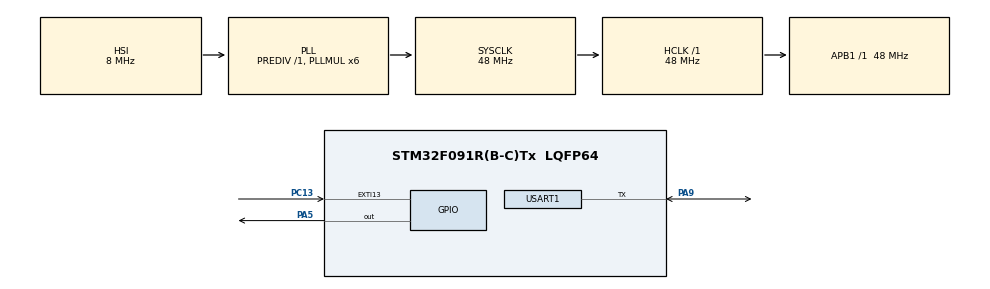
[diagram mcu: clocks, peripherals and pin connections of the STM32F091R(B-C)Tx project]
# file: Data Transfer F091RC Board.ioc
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Dma.Request0=USART1_RX
Dma.Request1=USART1_TX
Dma.USART1_RX.0.Direction=DMA_PERIPH_TO_MEMORY
Dma.USART1_RX.0.Instance=DMA1_Channel1
Dma.USART1_RX.0.MemDataAlignment=DMA_MDATAALIGN_BYTE
Dma.USART1_RX.0.MemInc=DMA_MINC_ENABLE
Dma.USART1_RX.0.Mode=DMA_NORMAL
Dma.USART1_RX.0.PeriphDataAlignment=DMA_PDATAALIGN_BYTE
Dma.USART1_RX.0.PeriphInc=DMA_PINC_DISABLE
Dma.USART1_RX.0.Priority=DMA_PRIORITY_LOW
Dma.USART1_TX.1.Direction=DMA_MEMORY_TO_PERIPH
Dma.USART1_TX.1.Instance=DMA1_Channel2
Dma.USART1_TX.1.MemDataAlignment=DMA_MDATAALIGN_BYTE
Dma.USART1_TX.1.MemInc=DMA_MINC_ENABLE
Dma.USART1_TX.1.Mode=DMA_NORMAL
Dma.USART1_TX.1.PeriphDataAlignment=DMA_PDATAALIGN_BYTE
Dma.USART1_TX.1.PeriphInc=DMA_PINC_DISABLE
Dma.USART1_TX.1.Priority=DMA_PRIORITY_LOW
Mcu.Family=STM32F0
Mcu.Name=STM32F091R(B-C)Tx
Mcu.Package=LQFP64
NVIC.DMA1_Ch1_IRQn=true\:0\:0\:false\:false\:true\:false\:true\:true
NVIC.DMA1_Ch2_3_DMA2_Ch1_2_IRQn=true\:0\:0\:false\:false\:true\:false\:true\:true
NVIC.EXTI4_15_IRQn=true\:0\:0\:false\:false\:true\:true\:true\:true
NVIC.USART1_IRQn=true\:0\:0\:false\:false\:true\:true\:true\:true
PA13.GPIO_Label=TMS
PA13.Mode=Serial_Wire
PA13.Signal=SYS_SWDIO
PA14.GPIO_Label=TCK
PA14.Mode=Serial_Wire
PA14.Signal=SYS_SWCLK
PA3.GPIO_Label=USART_RX
PA3.GPIO_Mode=GPIO_MODE_AF_PP
PA3.GPIO_PuPd=GPIO_NOPULL
PA3.GPIO_Speed=GPIO_SPEED_FREQ_LOW
PA3.Signal=USART2_RX
PA5.Signal=GPIO_Output
PA9.Mode=Half_duplex(single_wire_mode)
PA9.Signal=USART1_TX
PC13.GPIO_ModeDefaultEXTI=GPIO_MODE_IT_RISING
PC13.GPIO_PuPd=GPIO_PULLUP
PC13.Signal=GPXTI13
PC14OSC32_IN.Mode=LSE-External-Oscillator
PC14OSC32_IN.Signal=RCC_OSC32_IN
PC15OSC32_OUT.Mode=LSE-External-Oscillator
PC15OSC32_OUT.Signal=RCC_OSC32_OUT
PF0-OSC_IN.Mode=HSE-External-Clock-Source
PF0-OSC_IN.Signal=RCC_OSC_IN
PF1-OSC_OUT.Signal=RCC_OSC_OUT
ProjectManager.HeapSize=0x200
ProjectManager.StackSize=0x400
ProjectManager.TargetToolchain=STM32CubeIDE
RCC.AHBFreq_Value=48000000
RCC.APB1Freq_Value=48000000
RCC.APB1TimFreq_Value=48000000
RCC.FLatency-AdvancedSettings=FLASH_LATENCY_1
RCC.HCLKFreq_Value=48000000
RCC.PLLMUL=RCC_PLL_MUL6
RCC.PREFETCH_ENABLE-AdvancedSettings=1
RCC.SYSCLKFreq_VALUE=48000000
RCC.SYSCLKSource=RCC_SYSCLKSOURCE_PLLCLK
USART1.BaudRate=9600
USART1.VirtualMode-Half_duplex(single_wire_mode)=VM_ASYNC
board=NUCLEO-F091RC

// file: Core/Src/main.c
#include "main.h"
#include "stdio.h"

UART_HandleTypeDef huart1;
DMA_HandleTypeDef hdma_usart1_rx;
DMA_HandleTypeDef hdma_usart1_tx;

void SystemClock_Config(void);
static void MX_GPIO_Init(void);
static void MX_DMA_Init(void);
static void MX_USART1_UART_Init(void);
void DisplayHex(uint8_t value);

const uint8_t segmentMap[16] = {
	0b00111111, // 0
	0b00000110, // 1
	0b01011011, // 2
	0b01001111, // 3
	0b01100110, // 4
	0b01101101, // 5
	0b01111101, // 6
	0b00000111, // 7
	0b01111111, // 8
	0b01101111, // 9
	0b01110111, // A
	0b01111100, // B
	0b00111001, // C
	0b01011110, // D
	0b01111001, // E
	0b01110001  // F
};

typedef enum {
    STATE_IDLE,
    STATE_SEND_UART,
	STATE_PROCESS_RX
} SystemState_t;

SystemState_t currentState = STATE_IDLE;

uint8_t RxData[1];
uint8_t TxData[1];
uint8_t receivedValue = 0;
uint8_t rxFlag = 0;
uint8_t count = 0;
uint8_t isClicked = 0;

void HAL_UARTEx_RxEventCallback(UART_HandleTypeDef *huart, uint16_t Size)
{
	if (huart->Instance == USART1)
	    {
		receivedValue = RxData[0];
		rxFlag = 1;

		HAL_UARTEx_ReceiveToIdle_IT(&huart1, RxData, 1);
	    }
}

void HAL_GPIO_EXTI_Callback(uint16_t GPIO_Pin)
{
	if (GPIO_Pin == GPIO_PIN_13)
	{
		isClicked = 1;
	}
}

int main(void)
{
  HAL_Init();
  SystemClock_Config();
  MX_GPIO_Init();
  MX_DMA_Init();
  MX_USART1_UART_Init();

  HAL_HalfDuplex_EnableReceiver(&huart1);
  HAL_UARTEx_ReceiveToIdle_IT(&huart1, RxData, 1);

  DisplayHex(count);

  while (1)
  {
  switch (currentState)
	  {
	  case STATE_IDLE:
		  if (isClicked)
		  {
			  currentState = STATE_SEND_UART;
		  } else if (rxFlag)
		  {
			  currentState = STATE_PROCESS_RX;
		  }
		  break;

	  case STATE_SEND_UART:
	  {
		  HAL_Delay(100); // debounce

		  TxData[0] = count;
		  HAL_HalfDuplex_EnableTransmitter(&huart1);
		  HAL_UART_Transmit(&huart1, TxData, 1, 1000);
		  HAL_HalfDuplex_EnableReceiver(&huart1);

		  isClicked = 0;
		  currentState = STATE_IDLE;
		  break;
	   }

	  case STATE_PROCESS_RX:
	  {
		  count = receivedValue + 1;
		  if (count > 15)
		  {
			  count = 0;
		  }
		  DisplayHex(count);
		  rxFlag = 0;

		  currentState = STATE_IDLE;
		  break;
	  }

	  default:
		  currentState = STATE_IDLE;
		  break;
	  }
   }
}

void DisplayHex(uint8_t value)
{
    uint8_t segments = segmentMap[value];

    // PA0(A), PA1(B), PA4(E), PA5(F), PA6(G)
    HAL_GPIO_WritePin(GPIOA, GPIO_PIN_0, (segments & (1<<0)) ? GPIO_PIN_RESET : GPIO_PIN_SET);
    HAL_GPIO_WritePin(GPIOA, GPIO_PIN_1, (segments & (1<<1)) ? GPIO_PIN_RESET : GPIO_PIN_SET);
    HAL_GPIO_WritePin(GPIOA, GPIO_PIN_4, (segments & (1<<4)) ? GPIO_PIN_RESET : GPIO_PIN_SET);
    HAL_GPIO_WritePin(GPIOA, GPIO_PIN_5, (segments & (1<<5)) ? GPIO_PIN_RESET : GPIO_PIN_SET);
    HAL_GPIO_WritePin(GPIOA, GPIO_PIN_6, (segments & (1<<6)) ? GPIO_PIN_RESET : GPIO_PIN_SET);

    // PC10(C), PC11(D)
    HAL_GPIO_WritePin(GPIOC, GPIO_PIN_10, (segments & (1<<2)) ? GPIO_PIN_RESET : GPIO_PIN_SET);
    HAL_GPIO_WritePin(GPIOC, GPIO_PIN_11, (segments & (1<<3)) ? GPIO_PIN_RESET : GPIO_PIN_SET);
}

void SystemClock_Config(void)
{
  RCC_OscInitTypeDef RCC_OscInitStruct = {0};
  RCC_ClkInitTypeDef RCC_ClkInitStruct = {0};
  RCC_PeriphCLKInitTypeDef PeriphClkInit = {0};

  /** Initializes the RCC Oscillators according to the specified parameters
  * in the RCC_OscInitTypeDef structure.
  */
  RCC_OscInitStruct.OscillatorType = RCC_OSCILLATORTYPE_HSI;
  RCC_OscInitStruct.HSIState = RCC_HSI_ON;
  RCC_OscInitStruct.HSICalibrationValue = RCC_HSICALIBRATION_DEFAULT;
  RCC_OscInitStruct.PLL.PLLState = RCC_PLL_ON;
  RCC_OscInitStruct.PLL.PLLSource = RCC_PLLSOURCE_HSI;
  RCC_OscInitStruct.PLL.PLLMUL = RCC_PLL_MUL6;
  RCC_OscInitStruct.PLL.PREDIV = RCC_PREDIV_DIV1;
  if (HAL_RCC_OscConfig(&RCC_OscInitStruct) != HAL_OK)
  {
    Error_Handler();
  }

  /** Initializes the CPU, AHB and APB buses clocks
  */
  RCC_ClkInitStruct.ClockType = RCC_CLOCKTYPE_HCLK|RCC_CLOCKTYPE_SYSCLK
                              |RCC_CLOCKTYPE_PCLK1;
  RCC_ClkInitStruct.SYSCLKSource = RCC_SYSCLKSOURCE_PLLCLK;
  RCC_ClkInitStruct.AHBCLKDivider = RCC_SYSCLK_DIV1;
  RCC_ClkInitStruct.APB1CLKDivider = RCC_HCLK_DIV1;

  if (HAL_RCC_ClockConfig(&RCC_ClkInitStruct, FLASH_LATENCY_1) != HAL_OK)
  {
    Error_Handler();
  }
  PeriphClkInit.PeriphClockSelection = RCC_PERIPHCLK_USART1;
  PeriphClkInit.Usart1ClockSelection = RCC_USART1CLKSOURCE_PCLK1;
  if (HAL_RCCEx_PeriphCLKConfig(&PeriphClkInit) != HAL_OK)
  {
    Error_Handler();
  }
}

static void MX_USART1_UART_Init(void)
{
  huart1.Instance = USART1;
  huart1.Init.BaudRate = 9600;
  huart1.Init.WordLength = UART_WORDLENGTH_8B;
  huart1.Init.StopBits = UART_STOPBITS_1;
  huart1.Init.Parity = UART_PARITY_NONE;
  huart1.Init.Mode = UART_MODE_TX_RX;
  huart1.Init.HwFlowCtl = UART_HWCONTROL_NONE;
  huart1.Init.OverSampling = UART_OVERSAMPLING_16;
  huart1.Init.OneBitSampling = UART_ONE_BIT_SAMPLE_DISABLE;
  huart1.AdvancedInit.AdvFeatureInit = UART_ADVFEATURE_NO_INIT;
  if (HAL_HalfDuplex_Init(&huart1) != HAL_OK)
  {
    Error_Handler();
  }
}

static void MX_DMA_Init(void)
{

  /* DMA controller clock enable */
  __HAL_RCC_DMA1_CLK_ENABLE();

  /* DMA interrupt init */
  /* DMA1_Ch1_IRQn interrupt configuration */
  HAL_NVIC_SetPriority(DMA1_Ch1_IRQn, 0, 0);
  HAL_NVIC_EnableIRQ(DMA1_Ch1_IRQn);
  /* DMA1_Ch2_3_DMA2_Ch1_2_IRQn interrupt configuration */
  HAL_NVIC_SetPriority(DMA1_Ch2_3_DMA2_Ch1_2_IRQn, 0, 0);
  HAL_NVIC_EnableIRQ(DMA1_Ch2_3_DMA2_Ch1_2_IRQn);

}

static void MX_GPIO_Init(void)
{
  GPIO_InitTypeDef GPIO_InitStruct = {0};
  /* GPIO Ports Clock Enable */
  __HAL_RCC_GPIOC_CLK_ENABLE();
  __HAL_RCC_GPIOF_CLK_ENABLE();
  __HAL_RCC_GPIOA_CLK_ENABLE();
  __HAL_RCC_GPIOB_CLK_ENABLE();

  /*Configure GPIO pin Output Level */
  HAL_GPIO_WritePin(GPIOA, GPIO_PIN_5, GPIO_PIN_RESET);

  /*Configure GPIO pin : PC13 */
  GPIO_InitStruct.Pin = GPIO_PIN_13;
  GPIO_InitStruct.Mode = GPIO_MODE_IT_RISING;
  GPIO_InitStruct.Pull = GPIO_PULLUP;
  HAL_GPIO_Init(GPIOC, &GPIO_InitStruct);

  /*Configure GPIO pin : USART_RX_Pin */
  GPIO_InitStruct.Pin = USART_RX_Pin;
  GPIO_InitStruct.Mode = GPIO_MODE_AF_PP;
  GPIO_InitStruct.Pull = GPIO_NOPULL;
  GPIO_InitStruct.Speed = GPIO_SPEED_FREQ_LOW;
  GPIO_InitStruct.Alternate = GPIO_AF1_USART2;
  HAL_GPIO_Init(USART_RX_GPIO_Port, &GPIO_InitStruct);

  /* Configure GPIOA: PA0, PA1, PA4, PA5, PA6 as output */
  GPIO_InitStruct.Pin = GPIO_PIN_0 | GPIO_PIN_1 | GPIO_PIN_4 | GPIO_PIN_5 | GPIO_PIN_6;
  GPIO_InitStruct.Mode = GPIO_MODE_OUTPUT_PP;
  GPIO_InitStruct.Pull = GPIO_NOPULL;
  GPIO_InitStruct.Speed = GPIO_SPEED_FREQ_LOW;
  HAL_GPIO_Init(GPIOA, &GPIO_InitStruct);

  /* Configure GPIOC: PC10, PC11 as output */
  GPIO_InitStruct.Pin = GPIO_PIN_10 | GPIO_PIN_11;
  HAL_GPIO_Init(GPIOC, &GPIO_InitStruct);

  /* EXTI interrupt init*/
  HAL_NVIC_SetPriority(EXTI4_15_IRQn, 0, 0);
  HAL_NVIC_EnableIRQ(EXTI4_15_IRQn);
}

void Error_Handler(void)
{
  __disable_irq();
  while (1)
  {
  }
}
